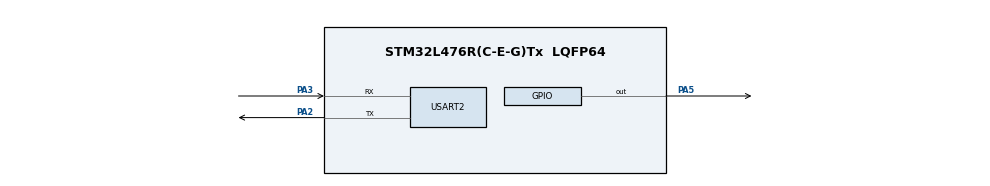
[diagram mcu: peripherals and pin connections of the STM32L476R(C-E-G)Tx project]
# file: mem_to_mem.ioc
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Dma.MEMTOMEM.0.Direction=DMA_MEMORY_TO_MEMORY
Dma.MEMTOMEM.0.Instance=DMA1_Channel1
Dma.MEMTOMEM.0.MemDataAlignment=DMA_MDATAALIGN_BYTE
Dma.MEMTOMEM.0.MemInc=DMA_MINC_ENABLE
Dma.MEMTOMEM.0.Mode=DMA_NORMAL
Dma.MEMTOMEM.0.PeriphDataAlignment=DMA_PDATAALIGN_BYTE
Dma.MEMTOMEM.0.PeriphInc=DMA_PINC_ENABLE
Dma.MEMTOMEM.0.Priority=DMA_PRIORITY_LOW
Dma.Request0=MEMTOMEM
Mcu.Family=STM32L4
Mcu.Name=STM32L476R(C-E-G)Tx
Mcu.Package=LQFP64
NVIC.DMA1_Channel1_IRQn=true\:0\:0\:false\:false\:true\:true\:true\:true
NVIC.PriorityGroup=NVIC_PRIORITYGROUP_4
PA2.Mode=Asynchronous
PA2.Signal=USART2_TX
PA3.Mode=Asynchronous
PA3.Signal=USART2_RX
PA5.Signal=GPIO_Output
PC14-OSC32_IN\ (PC14).Mode=LSE-External-Oscillator
PC14-OSC32_IN\ (PC14).Signal=RCC_OSC32_IN
PC15-OSC32_OUT\ (PC15).Mode=LSE-External-Oscillator
PC15-OSC32_OUT\ (PC15).Signal=RCC_OSC32_OUT
ProjectManager.HeapSize=0x200
ProjectManager.StackSize=0x400
ProjectManager.TargetToolchain=STM32CubeIDE
RCC.HSE_VALUE=8000000
RCC.HSI_VALUE=16000000
RCC.MSI_VALUE=4000000
RCC.VCOOutputFreq_Value=32000000
USART2.VirtualMode-Asynchronous=VM_ASYNC
board=custom

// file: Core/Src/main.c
/* USER CODE BEGIN Header */
/**
  ******************************************************************************
  * @file           : main.c
  * @brief          : DMA Memory to Memory Example
  ******************************************************************************
  */
/* USER CODE END Header */

#include "main.h"
#include <string.h>

UART_HandleTypeDef huart2;
DMA_HandleTypeDef hdma_memtomem_dma1_channel1;

/* USER CODE BEGIN PV */
uint8_t srcBuffer[100];
uint8_t dstBuffer[100];
uint8_t transferComplete = 0;
/* USER CODE END PV */

void SystemClock_Config(void);
static void MX_GPIO_Init(void);
static void MX_DMA_Init(void);
static void MX_USART2_UART_Init(void);

/* USER CODE BEGIN 0 */

/* DMA Transfer Complete Callback */
void HAL_DMA_XferCpltCallback(DMA_HandleTypeDef *hdma)
{
    if(hdma->Instance == DMA1_Channel1)
    {
        transferComplete = 1;

        char msg[] = "DMA Transfer Completed\r\n";
        HAL_UART_Transmit(&huart2, (uint8_t*)msg, sizeof(msg)-1, HAL_MAX_DELAY);
    }
}

/* USER CODE END 0 */

int main(void)
{
  HAL_Init();
  SystemClock_Config();

  MX_GPIO_Init();
  MX_DMA_Init();
  MX_USART2_UART_Init();

  /* USER CODE BEGIN 2 */

  // Fill source buffer
  for(int i = 0; i < 100; i++)
  {
      srcBuffer[i] = i;
  }

  // Start DMA Memory to Memory transfer
  HAL_DMA_Start_IT(&hdma_memtomem_dma1_channel1,
                   (uint32_t)srcBuffer,
                   (uint32_t)dstBuffer,
                   100);

  /* USER CODE END 2 */

  while (1)
  {
      if(transferComplete)
      {
    	  HAL_GPIO_TogglePin(GPIOA, GPIO_PIN_5);
          HAL_Delay(500);
      }
  }
}

/* System Clock Configuration */
void SystemClock_Config(void)
{
  RCC_OscInitTypeDef RCC_OscInitStruct = {0};
  RCC_ClkInitTypeDef RCC_ClkInitStruct = {0};

  HAL_PWREx_ControlVoltageScaling(PWR_REGULATOR_VOLTAGE_SCALE1);

  RCC_OscInitStruct.OscillatorType = RCC_OSCILLATORTYPE_HSI;
  RCC_OscInitStruct.HSIState = RCC_HSI_ON;
  RCC_OscInitStruct.PLL.PLLState = RCC_PLL_ON;
  RCC_OscInitStruct.PLL.PLLSource = RCC_PLLSOURCE_HSI;
  RCC_OscInitStruct.PLL.PLLM = 1;
  RCC_OscInitStruct.PLL.PLLN = 10;
  RCC_OscInitStruct.PLL.PLLR = RCC_PLLR_DIV2;
  HAL_RCC_OscConfig(&RCC_OscInitStruct);

  RCC_ClkInitStruct.ClockType = RCC_CLOCKTYPE_SYSCLK|
                                RCC_CLOCKTYPE_HCLK|
                                RCC_CLOCKTYPE_PCLK1|
                                RCC_CLOCKTYPE_PCLK2;

  RCC_ClkInitStruct.SYSCLKSource = RCC_SYSCLKSOURCE_PLLCLK;
  RCC_ClkInitStruct.AHBCLKDivider = RCC_SYSCLK_DIV1;
  RCC_ClkInitStruct.APB1CLKDivider = RCC_HCLK_DIV1;
  RCC_ClkInitStruct.APB2CLKDivider = RCC_HCLK_DIV1;

  HAL_RCC_ClockConfig(&RCC_ClkInitStruct, FLASH_LATENCY_4);
}

/* USART2 Init */
static void MX_USART2_UART_Init(void)
{
  huart2.Instance = USART2;
  huart2.Init.BaudRate = 115200;
  huart2.Init.WordLength = UART_WORDLENGTH_8B;
  huart2.Init.StopBits = UART_STOPBITS_1;
  huart2.Init.Parity = UART_PARITY_NONE;
  huart2.Init.Mode = UART_MODE_TX_RX;
  huart2.Init.HwFlowCtl = UART_HWCONTROL_NONE;
  huart2.Init.OverSampling = UART_OVERSAMPLING_16;

  HAL_UART_Init(&huart2);
}

/* DMA Init */
static void MX_DMA_Init(void)
{
  __HAL_RCC_DMA1_CLK_ENABLE();

  hdma_memtomem_dma1_channel1.Instance = DMA1_Channel1;
  hdma_memtomem_dma1_channel1.Init.Request = DMA_REQUEST_0;
  hdma_memtomem_dma1_channel1.Init.Direction = DMA_MEMORY_TO_MEMORY;
  hdma_memtomem_dma1_channel1.Init.PeriphInc = DMA_PINC_ENABLE;
  hdma_memtomem_dma1_channel1.Init.MemInc = DMA_MINC_ENABLE;
  hdma_memtomem_dma1_channel1.Init.PeriphDataAlignment = DMA_PDATAALIGN_BYTE;
  hdma_memtomem_dma1_channel1.Init.MemDataAlignment = DMA_MDATAALIGN_BYTE;
  hdma_memtomem_dma1_channel1.Init.Mode = DMA_NORMAL;
  hdma_memtomem_dma1_channel1.Init.Priority = DMA_PRIORITY_HIGH;

  HAL_DMA_Init(&hdma_memtomem_dma1_channel1);

  HAL_NVIC_SetPriority(DMA1_Channel1_IRQn, 0, 0);
  HAL_NVIC_EnableIRQ(DMA1_Channel1_IRQn);
}

/* GPIO Init */
static void MX_GPIO_Init(void)
{
  __HAL_RCC_GPIOA_CLK_ENABLE();

  GPIO_InitTypeDef GPIO_InitStruct = {0};

  GPIO_InitStruct.Pin = GPIO_PIN_5;
  GPIO_InitStruct.Mode = GPIO_MODE_OUTPUT_PP;
  GPIO_InitStruct.Pull = GPIO_NOPULL;
  GPIO_InitStruct.Speed = GPIO_SPEED_FREQ_LOW;

}

/* DMA IRQ Handler */
//void DMA1_Channel1_IRQHandler(void)
//{
//  HAL_DMA_IRQHandler(&hdma_memtomem_dma1_channel1);
//}

/* Error Handler */
void Error_Handler(void)
{
  __disable_irq();
  while (1)
  {
  }
}
